VERSION 5.7 ;
  NOWIREEXTENSIONATPIN ON ;
  DIVIDERCHAR "/" ;
  BUSBITCHARS "[]" ;
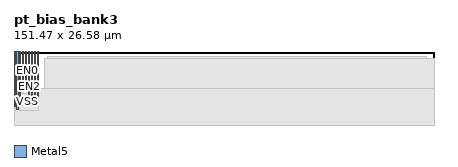
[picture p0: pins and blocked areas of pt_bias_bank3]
MACRO pt_bias_bank3
  CLASS BLOCK ;
  FOREIGN pt_bias_bank3 ;
  ORIGIN -0.300 25.360 ;
  SIZE 151.470 BY 26.580 ;
  PIN VDD
    DIRECTION INOUT ;
    USE POWER ;
    PORT
      LAYER Metal5 ;
        RECT 0.300 -18.720 0.740 1.220 ;
    END
  END VDD
  PIN VSS
    DIRECTION INOUT ;
    USE GROUND ;
    PORT
      LAYER Metal5 ;
        RECT 1.340 -19.620 1.780 1.220 ;
    END
  END VSS
  PIN TRK
    DIRECTION INPUT ;
    USE SIGNAL ;
    ANTENNAGATEAREA 160.000000 ;
    ANTENNADIFFAREA 2.600000 ;
    PORT
      LAYER Metal5 ;
        RECT 2.380 -17.820 2.820 1.220 ;
    END
  END TRK
  PIN EN0
    DIRECTION INPUT ;
    USE SIGNAL ;
    ANTENNAGATEAREA 3.360000 ;
    PORT
      LAYER Metal5 ;
        RECT 3.420 -12.420 3.860 1.220 ;
    END
  END EN0
  PIN EN1
    DIRECTION INPUT ;
    USE SIGNAL ;
    ANTENNAGATEAREA 3.360000 ;
    PORT
      LAYER Metal5 ;
        RECT 4.460 -13.320 4.900 1.220 ;
    END
  END EN1
  PIN EN2
    DIRECTION INPUT ;
    USE SIGNAL ;
    ANTENNAGATEAREA 3.360000 ;
    PORT
      LAYER Metal5 ;
        RECT 5.500 -14.220 5.940 1.220 ;
    END
  END EN2
  PIN OUT0
    DIRECTION OUTPUT ;
    USE SIGNAL ;
    ANTENNADIFFAREA 3.520000 ;
    PORT
      LAYER Metal5 ;
        RECT 6.540 -15.120 6.980 1.220 ;
    END
  END OUT0
  PIN OUT1
    DIRECTION OUTPUT ;
    USE SIGNAL ;
    ANTENNADIFFAREA 3.520000 ;
    PORT
      LAYER Metal5 ;
        RECT 7.580 -16.020 8.020 1.220 ;
    END
  END OUT1
  PIN OUT2
    DIRECTION OUTPUT ;
    USE SIGNAL ;
    ANTENNADIFFAREA 3.520000 ;
    PORT
      LAYER Metal5 ;
        RECT 8.620 -16.920 9.060 1.220 ;
    END
  END OUT2
  OBS
      LAYER Nwell ;
        RECT 12.210 -11.160 149.170 -0.600 ;
      LAYER Metal1 ;
        RECT 12.395 -11.060 149.070 -0.785 ;
      LAYER Metal2 ;
        RECT 11.310 -11.060 151.770 -1.360 ;
      LAYER Metal3 ;
        RECT 11.310 -25.360 151.770 -1.360 ;
      LAYER Metal4 ;
        RECT 0.320 -25.360 151.770 -12.360 ;
      LAYER Metal5 ;
        RECT 3.420 -13.920 3.860 -13.020 ;
        RECT 3.420 -14.820 4.900 -13.920 ;
        RECT 3.420 -15.720 5.940 -14.820 ;
        RECT 3.420 -16.620 6.980 -15.720 ;
        RECT 3.420 -17.520 8.020 -16.620 ;
        RECT 3.420 -18.420 9.060 -17.520 ;
        RECT 0.300 -19.000 0.380 -18.720 ;
        RECT 0.300 -19.080 0.740 -19.000 ;
        RECT 0.300 -19.980 0.740 -19.320 ;
        RECT 2.380 -19.980 9.060 -18.420 ;
  END
END pt_bias_bank3
END LIBRARY

